One B-rep face of a CAD part: STEP entity #69234.
In plain terms, the planar face has unit normal (0, 0, 1).
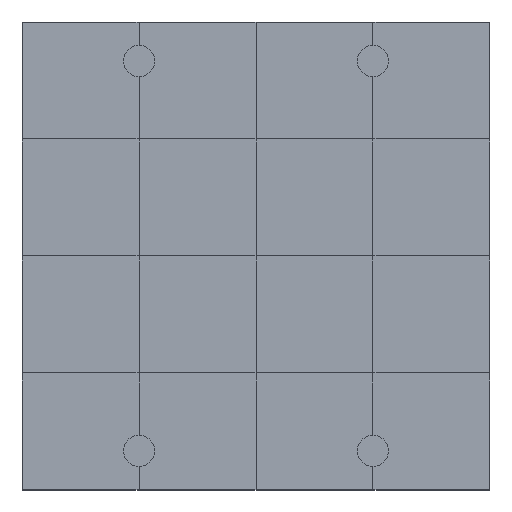
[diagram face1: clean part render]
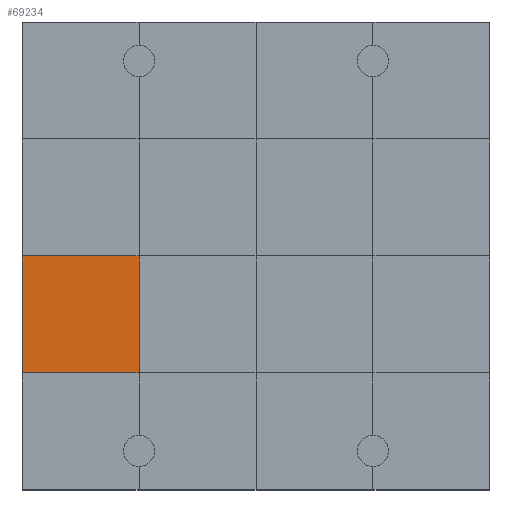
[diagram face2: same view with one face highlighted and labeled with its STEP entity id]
Its self-contained STEP definition (entity closure, numbers rounded to 3 decimals):
#68784 = VERTEX_POINT('',#68785);
#68785 = CARTESIAN_POINT('',(0.,3.,1.2));
#68799 = PLANE('',#68800);
#68800 = AXIS2_PLACEMENT_3D('',#68801,#68802,#68803);
#68801 = CARTESIAN_POINT('',(0.,3.,0.));
#68802 = DIRECTION('',(1.,0.,-0.));
#68803 = DIRECTION('',(0.,0.,1.));
#68825 = PLANE('',#68826);
#68826 = AXIS2_PLACEMENT_3D('',#68827,#68828,#68829);
#68827 = CARTESIAN_POINT('',(0.,0.,1.2));
#68828 = DIRECTION('',(0.,0.,1.));
#68829 = DIRECTION('',(1.,0.,-0.));
#68976 = VERTEX_POINT('',#68977);
#68977 = CARTESIAN_POINT('',(3.,3.,1.2));
#68998 = EDGE_CURVE('',#68784,#68976,#68999,.T.);
#68999 = SURFACE_CURVE('',#69000,(#69004,#69011),.PCURVE_S1.);
#69000 = LINE('',#69001,#69002);
#69001 = CARTESIAN_POINT('',(0.,3.,1.2));
#69002 = VECTOR('',#69003,1.);
#69003 = DIRECTION('',(1.,0.,-0.));
#69004 = PCURVE('',#68825,#69005);
#69005 = DEFINITIONAL_REPRESENTATION('',(#69006),#69010);
#69006 = LINE('',#69007,#69008);
#69007 = CARTESIAN_POINT('',(0.,3.));
#69008 = VECTOR('',#69009,1.);
#69009 = DIRECTION('',(1.,0.));
#69010 = ( GEOMETRIC_REPRESENTATION_CONTEXT(2) 
PARAMETRIC_REPRESENTATION_CONTEXT() REPRESENTATION_CONTEXT('2D SPACE',''
  ) );
#69011 = PCURVE('',#69012,#69017);
#69012 = PLANE('',#69013);
#69013 = AXIS2_PLACEMENT_3D('',#69014,#69015,#69016);
#69014 = CARTESIAN_POINT('',(0.,3.,1.2));
#69015 = DIRECTION('',(0.,0.,1.));
#69016 = DIRECTION('',(1.,0.,-0.));
#69017 = DEFINITIONAL_REPRESENTATION('',(#69018),#69022);
#69018 = LINE('',#69019,#69020);
#69019 = CARTESIAN_POINT('',(0.,0.));
#69020 = VECTOR('',#69021,1.);
#69021 = DIRECTION('',(1.,0.));
#69022 = ( GEOMETRIC_REPRESENTATION_CONTEXT(2) 
PARAMETRIC_REPRESENTATION_CONTEXT() REPRESENTATION_CONTEXT('2D SPACE',''
  ) );
#69057 = VERTEX_POINT('',#69058);
#69058 = CARTESIAN_POINT('',(0.,6.,1.2));
#69084 = EDGE_CURVE('',#68784,#69057,#69085,.T.);
#69085 = SURFACE_CURVE('',#69086,(#69090,#69097),.PCURVE_S1.);
#69086 = LINE('',#69087,#69088);
#69087 = CARTESIAN_POINT('',(0.,3.,1.2));
#69088 = VECTOR('',#69089,1.);
#69089 = DIRECTION('',(-0.,1.,0.));
#69090 = PCURVE('',#68799,#69091);
#69091 = DEFINITIONAL_REPRESENTATION('',(#69092),#69096);
#69092 = LINE('',#69093,#69094);
#69093 = CARTESIAN_POINT('',(1.2,0.));
#69094 = VECTOR('',#69095,1.);
#69095 = DIRECTION('',(0.,-1.));
#69096 = ( GEOMETRIC_REPRESENTATION_CONTEXT(2) 
PARAMETRIC_REPRESENTATION_CONTEXT() REPRESENTATION_CONTEXT('2D SPACE',''
  ) );
#69097 = PCURVE('',#69012,#69098);
#69098 = DEFINITIONAL_REPRESENTATION('',(#69099),#69103);
#69099 = LINE('',#69100,#69101);
#69100 = CARTESIAN_POINT('',(0.,0.));
#69101 = VECTOR('',#69102,1.);
#69102 = DIRECTION('',(0.,1.));
#69103 = ( GEOMETRIC_REPRESENTATION_CONTEXT(2) 
PARAMETRIC_REPRESENTATION_CONTEXT() REPRESENTATION_CONTEXT('2D SPACE',''
  ) );
#69234 = ADVANCED_FACE('',(#69235),#69012,.T.);
#69235 = FACE_BOUND('',#69236,.T.);
#69236 = EDGE_LOOP('',(#69237,#69238,#69239,#69267));
#69237 = ORIENTED_EDGE('',*,*,#69084,.F.);
#69238 = ORIENTED_EDGE('',*,*,#68998,.T.);
#69239 = ORIENTED_EDGE('',*,*,#69240,.T.);
#69240 = EDGE_CURVE('',#68976,#69241,#69243,.T.);
#69241 = VERTEX_POINT('',#69242);
#69242 = CARTESIAN_POINT('',(3.,6.,1.2));
#69243 = SURFACE_CURVE('',#69244,(#69248,#69255),.PCURVE_S1.);
#69244 = LINE('',#69245,#69246);
#69245 = CARTESIAN_POINT('',(3.,3.,1.2));
#69246 = VECTOR('',#69247,1.);
#69247 = DIRECTION('',(-0.,1.,0.));
#69248 = PCURVE('',#69012,#69249);
#69249 = DEFINITIONAL_REPRESENTATION('',(#69250),#69254);
#69250 = LINE('',#69251,#69252);
#69251 = CARTESIAN_POINT('',(3.,0.));
#69252 = VECTOR('',#69253,1.);
#69253 = DIRECTION('',(0.,1.));
#69254 = ( GEOMETRIC_REPRESENTATION_CONTEXT(2) 
PARAMETRIC_REPRESENTATION_CONTEXT() REPRESENTATION_CONTEXT('2D SPACE',''
  ) );
#69255 = PCURVE('',#69256,#69261);
#69256 = PLANE('',#69257);
#69257 = AXIS2_PLACEMENT_3D('',#69258,#69259,#69260);
#69258 = CARTESIAN_POINT('',(3.,3.,1.2));
#69259 = DIRECTION('',(0.,0.,1.));
#69260 = DIRECTION('',(1.,0.,-0.));
#69261 = DEFINITIONAL_REPRESENTATION('',(#69262),#69266);
#69262 = LINE('',#69263,#69264);
#69263 = CARTESIAN_POINT('',(0.,0.));
#69264 = VECTOR('',#69265,1.);
#69265 = DIRECTION('',(0.,1.));
#69266 = ( GEOMETRIC_REPRESENTATION_CONTEXT(2) 
PARAMETRIC_REPRESENTATION_CONTEXT() REPRESENTATION_CONTEXT('2D SPACE',''
  ) );
#69267 = ORIENTED_EDGE('',*,*,#69268,.F.);
#69268 = EDGE_CURVE('',#69057,#69241,#69269,.T.);
#69269 = SURFACE_CURVE('',#69270,(#69274,#69281),.PCURVE_S1.);
#69270 = LINE('',#69271,#69272);
#69271 = CARTESIAN_POINT('',(0.,6.,1.2));
#69272 = VECTOR('',#69273,1.);
#69273 = DIRECTION('',(1.,0.,-0.));
#69274 = PCURVE('',#69012,#69275);
#69275 = DEFINITIONAL_REPRESENTATION('',(#69276),#69280);
#69276 = LINE('',#69277,#69278);
#69277 = CARTESIAN_POINT('',(0.,3.));
#69278 = VECTOR('',#69279,1.);
#69279 = DIRECTION('',(1.,0.));
#69280 = ( GEOMETRIC_REPRESENTATION_CONTEXT(2) 
PARAMETRIC_REPRESENTATION_CONTEXT() REPRESENTATION_CONTEXT('2D SPACE',''
  ) );
#69281 = PCURVE('',#69282,#69287);
#69282 = PLANE('',#69283);
#69283 = AXIS2_PLACEMENT_3D('',#69284,#69285,#69286);
#69284 = CARTESIAN_POINT('',(0.,6.,1.2));
#69285 = DIRECTION('',(0.,0.,1.));
#69286 = DIRECTION('',(1.,0.,-0.));
#69287 = DEFINITIONAL_REPRESENTATION('',(#69288),#69292);
#69288 = LINE('',#69289,#69290);
#69289 = CARTESIAN_POINT('',(0.,0.));
#69290 = VECTOR('',#69291,1.);
#69291 = DIRECTION('',(1.,0.));
#69292 = ( GEOMETRIC_REPRESENTATION_CONTEXT(2) 
PARAMETRIC_REPRESENTATION_CONTEXT() REPRESENTATION_CONTEXT('2D SPACE',''
  ) );
